One B-rep face of a CAD part: STEP entity #741.
In plain terms, the planar face has unit normal (1, 0, 0).
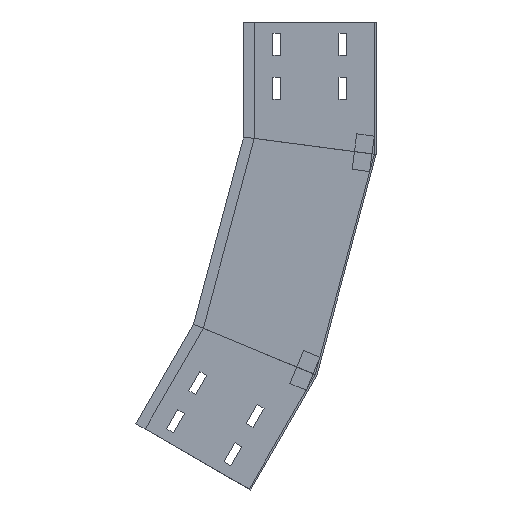
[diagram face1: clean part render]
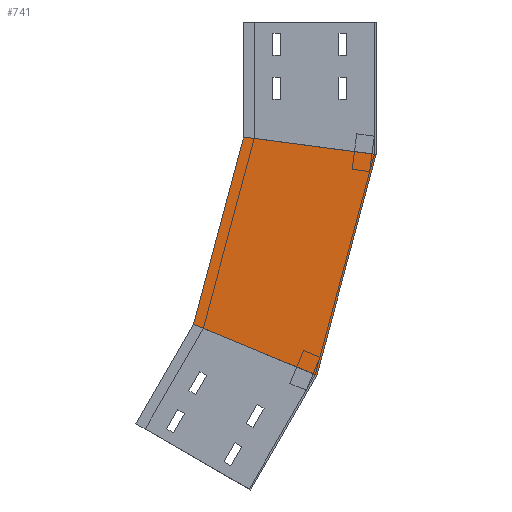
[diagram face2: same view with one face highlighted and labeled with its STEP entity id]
Its self-contained STEP definition (entity closure, numbers rounded to 3 decimals):
#13 = CARTESIAN_POINT ( 'NONE',  ( 0., 0., -150. ) ) ;
#23 = DIRECTION ( 'NONE',  ( 0., -0.924, -0.383 ) ) ;
#33 = DIRECTION ( 'NONE',  ( 0., 0., 1. ) ) ;
#138 = VERTEX_POINT ( 'NONE', #472 ) ;
#199 = PLANE ( 'NONE',  #362 ) ;
#210 = DIRECTION ( 'NONE',  ( 0., -0.991, -0.131 ) ) ;
#231 = VECTOR ( 'NONE', #23, 1000. ) ;
#313 = EDGE_CURVE ( 'NONE', #709, #1199, #1581, .T. ) ;
#320 = LINE ( 'NONE', #1557, #619 ) ;
#362 = AXIS2_PLACEMENT_3D ( 'NONE', #13, #814, #33 ) ;
#472 = CARTESIAN_POINT ( 'NONE',  ( 0., 150., -130.252 ) ) ;
#553 = DIRECTION ( 'NONE',  ( 0., 0.259, -0.966 ) ) ;
#618 = DIRECTION ( 'NONE',  ( 0., 0.259, -0.966 ) ) ;
#619 = VECTOR ( 'NONE', #618, 1000. ) ;
#680 = EDGE_CURVE ( 'NONE', #138, #1382, #1744, .T. ) ;
#709 = VERTEX_POINT ( 'NONE', #1147 ) ;
#741 = ADVANCED_FACE ( 'NONE', ( #1416 ), #199, .F. ) ;
#814 = DIRECTION ( 'NONE',  ( -1., 0., 0. ) ) ;
#1062 = EDGE_LOOP ( 'NONE', ( #1671, #1313, #1323, #1990 ) ) ;
#1105 = VECTOR ( 'NONE', #553, 1000. ) ;
#1119 = CARTESIAN_POINT ( 'NONE',  ( 0., 19.411, -147.444 ) ) ;
#1147 = CARTESIAN_POINT ( 'NONE',  ( 0., 206.812, -342.277 ) ) ;
#1154 = LINE ( 'NONE', #1932, #1105 ) ;
#1199 = VERTEX_POINT ( 'NONE', #1888 ) ;
#1313 = ORIENTED_EDGE ( 'NONE', *, *, #680, .T. ) ;
#1323 = ORIENTED_EDGE ( 'NONE', *, *, #1893, .T. ) ;
#1350 = EDGE_CURVE ( 'NONE', #138, #709, #1154, .T. ) ;
#1382 = VERTEX_POINT ( 'NONE', #1443 ) ;
#1416 = FACE_OUTER_BOUND ( 'NONE', #1062, .T. ) ;
#1420 = CARTESIAN_POINT ( 'NONE',  ( 0., 98.267, -387.238 ) ) ;
#1443 = CARTESIAN_POINT ( 'NONE',  ( 0., 0., -150. ) ) ;
#1557 = CARTESIAN_POINT ( 'NONE',  ( 0., 0., -150. ) ) ;
#1581 = LINE ( 'NONE', #1420, #231 ) ;
#1671 = ORIENTED_EDGE ( 'NONE', *, *, #1350, .F. ) ;
#1744 = LINE ( 'NONE', #1119, #1756 ) ;
#1756 = VECTOR ( 'NONE', #210, 1000. ) ;
#1888 = CARTESIAN_POINT ( 'NONE',  ( 0., 67.034, -400.175 ) ) ;
#1893 = EDGE_CURVE ( 'NONE', #1382, #1199, #320, .T. ) ;
#1932 = CARTESIAN_POINT ( 'NONE',  ( 0., 144.889, -111.177 ) ) ;
#1990 = ORIENTED_EDGE ( 'NONE', *, *, #313, .F. ) ;
